VERSION 5.7 ;
  NOWIREEXTENSIONATPIN ON ;
  DIVIDERCHAR "/" ;
  BUSBITCHARS "[]" ;
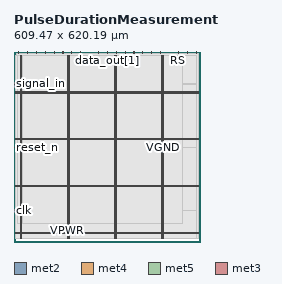
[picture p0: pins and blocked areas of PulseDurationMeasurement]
MACRO PulseDurationMeasurement
  CLASS BLOCK ;
  FOREIGN PulseDurationMeasurement ;
  ORIGIN 0.000 0.000 ;
  SIZE 609.470 BY 620.190 ;
  PIN EN
    DIRECTION INPUT ;
    USE SIGNAL ;
    ANTENNAGATEAREA 0.213000 ;
    PORT
      LAYER met2 ;
        RECT 594.410 616.190 594.690 620.190 ;
    END
  END EN
  PIN RS
    DIRECTION INPUT ;
    USE SIGNAL ;
    ANTENNAGATEAREA 0.247500 ;
    PORT
      LAYER met2 ;
        RECT 536.450 616.190 536.730 620.190 ;
    END
  END RS
  PIN RW
    DIRECTION INPUT ;
    USE SIGNAL ;
    ANTENNAGATEAREA 0.213000 ;
    PORT
      LAYER met2 ;
        RECT 565.430 616.190 565.710 620.190 ;
    END
  END RW
  PIN VGND
    DIRECTION INOUT ;
    USE GROUND ;
    PORT
      LAYER met4 ;
        RECT 24.340 10.640 25.940 609.520 ;
    END
    PORT
      LAYER met4 ;
        RECT 177.940 10.640 179.540 609.520 ;
    END
    PORT
      LAYER met4 ;
        RECT 331.540 10.640 333.140 609.520 ;
    END
    PORT
      LAYER met4 ;
        RECT 485.140 10.640 486.740 609.520 ;
    END
    PORT
      LAYER met5 ;
        RECT 5.280 30.030 603.760 31.630 ;
    END
    PORT
      LAYER met5 ;
        RECT 5.280 183.210 603.760 184.810 ;
    END
    PORT
      LAYER met5 ;
        RECT 5.280 336.390 603.760 337.990 ;
    END
    PORT
      LAYER met5 ;
        RECT 5.280 489.570 603.760 491.170 ;
    END
  END VGND
  PIN VPWR
    DIRECTION INOUT ;
    USE POWER ;
    PORT
      LAYER met4 ;
        RECT 21.040 10.640 22.640 609.520 ;
    END
    PORT
      LAYER met4 ;
        RECT 174.640 10.640 176.240 609.520 ;
    END
    PORT
      LAYER met4 ;
        RECT 328.240 10.640 329.840 609.520 ;
    END
    PORT
      LAYER met4 ;
        RECT 481.840 10.640 483.440 609.520 ;
    END
    PORT
      LAYER met5 ;
        RECT 5.280 26.730 603.760 28.330 ;
    END
    PORT
      LAYER met5 ;
        RECT 5.280 179.910 603.760 181.510 ;
    END
    PORT
      LAYER met5 ;
        RECT 5.280 333.090 603.760 334.690 ;
    END
    PORT
      LAYER met5 ;
        RECT 5.280 486.270 603.760 487.870 ;
    END
  END VPWR
  PIN clk
    DIRECTION INPUT ;
    USE SIGNAL ;
    ANTENNAGATEAREA 0.852000 ;
    ANTENNADIFFAREA 0.434700 ;
    PORT
      LAYER met3 ;
        RECT 0.000 102.040 4.000 102.640 ;
    END
  END clk
  PIN data_in[0]
    DIRECTION INPUT ;
    USE SIGNAL ;
    ANTENNAGATEAREA 0.247500 ;
    PORT
      LAYER met2 ;
        RECT 14.810 616.190 15.090 620.190 ;
    END
  END data_in[0]
  PIN data_in[1]
    DIRECTION INPUT ;
    USE SIGNAL ;
    ANTENNAGATEAREA 0.247500 ;
    PORT
      LAYER met2 ;
        RECT 43.790 616.190 44.070 620.190 ;
    END
  END data_in[1]
  PIN data_in[2]
    DIRECTION INPUT ;
    USE SIGNAL ;
    ANTENNAGATEAREA 0.247500 ;
    PORT
      LAYER met2 ;
        RECT 72.770 616.190 73.050 620.190 ;
    END
  END data_in[2]
  PIN data_in[3]
    DIRECTION INPUT ;
    USE SIGNAL ;
    ANTENNAGATEAREA 0.247500 ;
    PORT
      LAYER met2 ;
        RECT 101.750 616.190 102.030 620.190 ;
    END
  END data_in[3]
  PIN data_in[4]
    DIRECTION INPUT ;
    USE SIGNAL ;
    ANTENNAGATEAREA 0.213000 ;
    PORT
      LAYER met2 ;
        RECT 130.730 616.190 131.010 620.190 ;
    END
  END data_in[4]
  PIN data_in[5]
    DIRECTION INPUT ;
    USE SIGNAL ;
    ANTENNAGATEAREA 0.247500 ;
    PORT
      LAYER met2 ;
        RECT 159.710 616.190 159.990 620.190 ;
    END
  END data_in[5]
  PIN data_in[6]
    DIRECTION INPUT ;
    USE SIGNAL ;
    ANTENNAGATEAREA 0.213000 ;
    PORT
      LAYER met2 ;
        RECT 188.690 616.190 188.970 620.190 ;
    END
  END data_in[6]
  PIN data_in[7]
    DIRECTION INPUT ;
    USE SIGNAL ;
    ANTENNAGATEAREA 0.213000 ;
    PORT
      LAYER met2 ;
        RECT 217.670 616.190 217.950 620.190 ;
    END
  END data_in[7]
  PIN data_out[0]
    DIRECTION OUTPUT TRISTATE ;
    USE SIGNAL ;
    ANTENNADIFFAREA 0.795200 ;
    PORT
      LAYER met2 ;
        RECT 275.630 616.190 275.910 620.190 ;
    END
  END data_out[0]
  PIN data_out[1]
    DIRECTION OUTPUT TRISTATE ;
    USE SIGNAL ;
    ANTENNADIFFAREA 0.445500 ;
    PORT
      LAYER met2 ;
        RECT 304.610 616.190 304.890 620.190 ;
    END
  END data_out[1]
  PIN data_out[2]
    DIRECTION OUTPUT TRISTATE ;
    USE SIGNAL ;
    ANTENNADIFFAREA 0.445500 ;
    PORT
      LAYER met2 ;
        RECT 333.590 616.190 333.870 620.190 ;
    END
  END data_out[2]
  PIN data_out[3]
    DIRECTION OUTPUT TRISTATE ;
    USE SIGNAL ;
    ANTENNADIFFAREA 0.795200 ;
    PORT
      LAYER met2 ;
        RECT 362.570 616.190 362.850 620.190 ;
    END
  END data_out[3]
  PIN data_out[4]
    DIRECTION OUTPUT TRISTATE ;
    USE SIGNAL ;
    ANTENNADIFFAREA 0.795200 ;
    PORT
      LAYER met2 ;
        RECT 391.550 616.190 391.830 620.190 ;
    END
  END data_out[4]
  PIN data_out[5]
    DIRECTION OUTPUT TRISTATE ;
    USE SIGNAL ;
    ANTENNADIFFAREA 0.795200 ;
    PORT
      LAYER met2 ;
        RECT 420.530 616.190 420.810 620.190 ;
    END
  END data_out[5]
  PIN data_out[6]
    DIRECTION OUTPUT TRISTATE ;
    USE SIGNAL ;
    ANTENNADIFFAREA 0.795200 ;
    PORT
      LAYER met2 ;
        RECT 449.510 616.190 449.790 620.190 ;
    END
  END data_out[6]
  PIN data_out[7]
    DIRECTION OUTPUT TRISTATE ;
    USE SIGNAL ;
    ANTENNADIFFAREA 0.795200 ;
    PORT
      LAYER met2 ;
        RECT 478.490 616.190 478.770 620.190 ;
    END
  END data_out[7]
  PIN reset_n
    DIRECTION INPUT ;
    USE SIGNAL ;
    ANTENNAGATEAREA 0.990000 ;
    PORT
      LAYER met3 ;
        RECT 0.000 308.760 4.000 309.360 ;
    END
  END reset_n
  PIN signal_in
    DIRECTION INPUT ;
    USE SIGNAL ;
    ANTENNAGATEAREA 0.213000 ;
    PORT
      LAYER met3 ;
        RECT 0.000 515.480 4.000 516.080 ;
    END
  END signal_in
  OBS
      LAYER li1 ;
        RECT 5.520 10.795 603.520 609.365 ;
      LAYER met1 ;
        RECT 5.520 10.640 603.820 610.260 ;
      LAYER met2 ;
        RECT 6.990 615.910 14.530 616.190 ;
        RECT 15.370 615.910 43.510 616.190 ;
        RECT 44.350 615.910 72.490 616.190 ;
        RECT 73.330 615.910 101.470 616.190 ;
        RECT 102.310 615.910 130.450 616.190 ;
        RECT 131.290 615.910 159.430 616.190 ;
        RECT 160.270 615.910 188.410 616.190 ;
        RECT 189.250 615.910 217.390 616.190 ;
        RECT 218.230 615.910 275.350 616.190 ;
        RECT 276.190 615.910 304.330 616.190 ;
        RECT 305.170 615.910 333.310 616.190 ;
        RECT 334.150 615.910 362.290 616.190 ;
        RECT 363.130 615.910 391.270 616.190 ;
        RECT 392.110 615.910 420.250 616.190 ;
        RECT 421.090 615.910 449.230 616.190 ;
        RECT 450.070 615.910 478.210 616.190 ;
        RECT 479.050 615.910 536.170 616.190 ;
        RECT 537.010 615.910 565.150 616.190 ;
        RECT 565.990 615.910 594.130 616.190 ;
        RECT 594.970 615.910 602.040 616.190 ;
        RECT 6.990 10.695 602.040 615.910 ;
      LAYER met3 ;
        RECT 3.990 516.480 596.095 609.445 ;
        RECT 4.400 515.080 596.095 516.480 ;
        RECT 3.990 309.760 596.095 515.080 ;
        RECT 4.400 308.360 596.095 309.760 ;
        RECT 3.990 103.040 596.095 308.360 ;
        RECT 4.400 101.640 596.095 103.040 ;
        RECT 3.990 10.715 596.095 101.640 ;
      LAYER met4 ;
        RECT 12.255 61.375 20.640 607.745 ;
        RECT 23.040 61.375 23.940 607.745 ;
        RECT 26.340 61.375 174.240 607.745 ;
        RECT 176.640 61.375 177.540 607.745 ;
        RECT 179.940 61.375 327.840 607.745 ;
        RECT 330.240 61.375 331.140 607.745 ;
        RECT 333.540 61.375 481.440 607.745 ;
        RECT 483.840 61.375 484.740 607.745 ;
        RECT 487.140 61.375 550.785 607.745 ;
  END
END PulseDurationMeasurement
END LIBRARY

